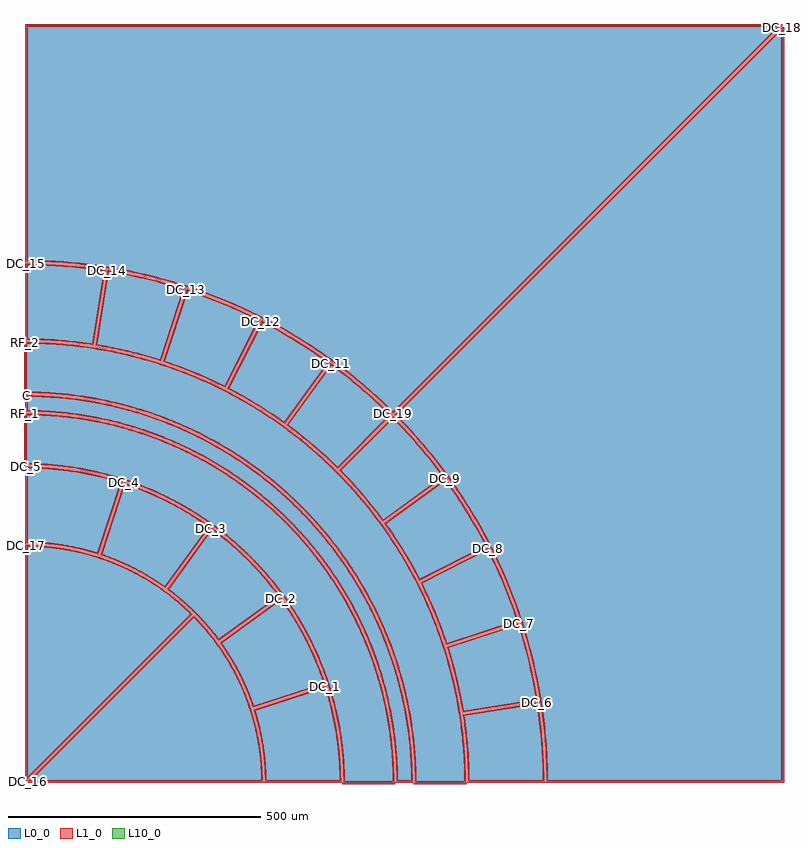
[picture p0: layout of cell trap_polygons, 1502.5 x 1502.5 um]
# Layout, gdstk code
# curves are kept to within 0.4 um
import gdstk
lib = gdstk.Library(unit=1e-6, precision=1e-09)
def P(c, l, *ps):  # polygons
    for p in ps: c.add(gdstk.Polygon(p, *l))
L0_0 = (0, 0)
L1_0 = (1, 0)
L10_0 = (10, 0)

trap_polygons = lib.new_cell('trap_polygons')
P(trap_polygons, L0_0, [(727.08,730.616),(691.717,764.181),(654.807,796.036),(609.899,830.945),(569.922,858.856),(528.671,884.846),(486.237,908.856),(442.715,930.833),(390.694,953.836),(345.151,971.245),(298.837,986.48),(251.854,999.508),(204.307,1010.299),(156.303,1018.83),(107.95,1025.082),(51.239,1029.476),(2.5,1030.747),(2.5,1497.5),(1493.964,1497.5)],
  [(1497.5,1493.964),(1497.5,2.5),(1030.747,2.5),(1029.476,51.239),(1025.082,107.95),(1018.83,156.303),(1010.299,204.307),(999.508,251.854),(986.48,298.837),(971.245,345.151),(953.836,390.694),(930.833,442.715),(908.856,486.237),(884.846,528.671),(858.856,569.922),(830.945,609.899),(796.036,654.807),(764.181,691.717),(730.616,727.08)],
  [(2.5,469.243),(28.188,468.403),(50.143,466.563),(71.986,463.695),(93.672,459.806),(115.15,454.902),(136.375,448.996),(160.754,440.856),(181.269,432.825),(201.385,423.839),(221.057,413.92),(240.241,403.088),(261.951,389.329),(279.936,376.605),(297.304,363.051),(314.017,348.696),(330.037,333.573),(2.5,6.036)],
  [(6.036,2.5),(333.573,330.037),(348.696,314.017),(363.051,297.304),(376.605,279.936),(389.329,261.951),(403.088,240.241),(413.92,221.057),(423.839,201.385),(432.825,181.269),(440.856,160.754),(448.996,136.375),(454.902,115.15),(459.806,93.672),(463.695,71.986),(466.563,50.143),(468.403,28.188),(469.243,2.5)],
  [(2.5,1025.747),(43.572,1024.824),(76.383,1022.902),(117.282,1019.023),(157.993,1013.509),(134.528,865.356),(99.959,870.027),(72.188,872.77),(37.374,874.952),(2.5,875.746)],
  [(162.931,1012.727),(203.354,1005.391),(235.46,998.36),(275.248,988.13),(314.596,976.316),(268.243,833.657),(234.831,843.678),(201.046,852.361),(173.786,858.334),(139.466,864.573)],
  [(319.351,974.771),(358.128,961.201),(396.33,946.09),(433.897,929.46),(463.452,915.082),(395.353,781.431),(370.254,793.631),(338.355,807.746),(305.919,820.58),(272.998,832.112)],
  [(467.907,912.812),(504.084,893.344),(539.452,872.442),(573.954,850.141),(600.896,831.316),(512.728,709.963),(484.048,729.819),(460.549,744.871),(430.52,762.621),(399.808,779.161)],
  [(604.941,828.377),(637.627,803.489),(669.29,777.312),(693.85,755.47),(723.545,727.08),(617.478,621.014),(592.258,645.112),(566.097,668.186),(544.52,685.884),(516.773,707.024)],
  [(727.08,723.545),(755.47,693.85),(777.312,669.29),(803.489,637.627),(828.377,604.941),(707.024,516.773),(685.884,544.52),(668.186,566.097),(645.112,592.258),(621.014,617.478)],
  [(831.316,600.896),(850.141,573.954),(872.442,539.452),(893.344,504.084),(912.812,467.907),(779.161,399.808),(762.621,430.52),(744.871,460.549),(729.819,484.048),(709.963,512.728)],
  [(915.082,463.452),(929.46,433.897),(946.09,396.33),(961.201,358.128),(974.771,319.351),(832.112,272.998),(820.58,305.919),(807.746,338.355),(793.631,370.254),(781.431,395.353)],
  [(976.316,314.596),(988.13,275.248),(998.36,235.46),(1005.391,203.354),(1012.727,162.931),(864.573,139.466),(858.334,173.786),(852.361,201.046),(843.678,234.831),(833.657,268.243)],
  [(1013.509,157.993),(1019.023,117.282),(1022.902,76.383),(1024.824,43.572),(1025.747,2.5),(875.746,2.5),(874.952,37.374),(872.77,72.188),(870.027,99.959),(865.356,134.528)],
  [(2.5,624.245),(26.993,623.666),(51.445,622.127),(95.233,616.943),(119.369,612.731),(143.32,607.575),(167.051,601.483),(190.525,594.465),(144.172,451.805),(108.597,461.649),(76.012,468.119),(39.375,472.613),(2.5,474.243)],
  [(195.28,592.92),(218.396,584.8),(241.175,575.78),(263.583,565.873),(285.585,555.094),(324.057,533.55),(344.744,520.423),(364.899,506.494),(276.731,385.14),(245.94,405.496),(213.659,423.395),(183.493,437.314),(148.927,450.26)],
  [(368.945,503.555),(403.571,476.255),(421.948,460.052),(439.675,443.141),(456.726,425.546),(473.072,407.297),(488.69,388.42),(503.555,368.945),(382.202,280.776),(361.607,306.844),(336.648,334.038),(309.65,359.207),(280.776,382.202)],
  [(506.494,364.899),(520.423,344.744),(533.55,324.057),(555.094,285.585),(565.873,263.583),(575.78,241.175),(584.8,218.396),(592.92,195.28),(450.26,148.927),(437.314,183.493),(423.395,213.659),(405.496,245.94),(385.14,276.731)],
  [(594.465,190.525),(601.483,167.051),(607.575,143.32),(612.731,119.369),(616.943,95.233),(622.127,51.445),(623.666,26.993),(624.245,2.5),(474.243,2.5),(472.613,39.375),(468.119,76.012),(461.649,108.597),(451.805,144.172)],
  [(2.5,765.746),(38.419,764.786),(80.212,761.537),(115.848,756.936),(151.229,750.668),(186.277,742.748),(226.642,731.441),(260.705,720.004),(294.194,706.981),(332.441,689.823),(364.435,673.469),(395.627,655.631),(425.947,636.35),(460.132,612.088),(488.339,589.829),(515.47,566.272),(541.467,541.467),(566.272,515.47),(589.829,488.339),(612.088,460.132),(636.35,425.947),(655.631,395.627),(673.469,364.435),(689.823,332.441),(706.981,294.194),(720.004,260.705),(731.441,226.642),(742.748,186.277),(750.668,151.229),(756.936,115.848),(761.537,80.212),(764.786,38.419),(765.746,2.5),(734.246,2.5),(733.009,42.668),(729.577,82.709),(723.959,122.502),(716.172,161.928),(706.24,200.869),(694.192,239.208),(680.065,276.83),(663.9,313.623),(648.46,344.417),(634.501,369.502),(616.472,398.855),(600.41,422.647),(579.926,450.343),(561.879,472.668),(542.973,494.27),(519.193,519.193),(494.27,542.973),(472.668,561.879),(450.343,579.926),(422.647,600.41),(398.855,616.472),(369.502,634.501),(344.417,648.46),(313.623,663.9),(276.83,680.065),(239.208,694.192),(200.869,706.24),(161.928,716.172),(122.502,723.959),(82.709,729.577),(42.668,733.009),(2.5,734.246)],
  [(0,870.75),(41.018,869.783),(81.945,866.886),(129.457,861.073),(169.875,854.019),(209.916,845.069),(256.036,832.257),(294.956,819.272),(333.222,804.468),(370.747,787.878),(407.45,769.539),(449.121,745.987),(483.763,724.002),(517.331,700.41),(549.75,675.263),(586.026,644.034),(615.713,615.713),(644.034,586.026),(675.263,549.75),(700.41,517.331),(724.002,483.763),(745.987,449.121),(769.539,407.45),(787.878,370.747),(804.468,333.222),(819.272,294.956),(832.257,256.036),(845.069,209.916),(854.019,169.875),(861.073,129.457),(866.886,81.945),(869.783,41.018),(870.75,0),(770.75,0),(769.894,36.307),(766.736,78.558),(762.184,114.589),(755.94,150.366),(748.018,185.809),(738.435,220.839),(727.212,255.379),(712.08,294.953),(694.797,333.637),(678.309,365.996),(660.315,397.542),(640.855,428.206),(619.973,457.919),(593.873,491.295),(570.071,518.724),(545.003,545.003),(518.724,570.071),(491.295,593.873),(457.919,619.973),(428.206,640.855),(397.542,660.315),(365.996,678.309),(333.637,694.797),(294.953,712.08),(255.379,727.212),(220.839,738.435),(185.809,748.018),(150.366,755.94),(114.589,762.184),(78.558,766.736),(36.307,769.894),(0,770.75)],
  [(0,729.25),(34.352,728.44),(68.628,726.014),(102.752,721.975),(142.27,715.238),(175.804,707.742),(208.948,698.675),(247.025,686.137),(279.072,673.739),(310.5,659.845),(341.238,644.486),(376.137,624.761),(405.15,606.349),(433.263,586.591),(464.841,561.897),(490.794,539.376),(515.658,515.658),(539.376,490.794),(561.897,464.841),(586.591,433.263),(606.349,405.15),(624.761,376.137),(644.486,341.238),(659.845,310.5),(673.739,279.072),(686.137,247.025),(698.675,208.948),(707.742,175.804),(715.238,142.27),(721.975,102.752),(726.014,68.628),(728.44,34.352),(729.25,0),(629.25,0),(628.299,34.577),(625.973,64.136),(622.257,93.552),(617.159,122.761),(609.481,156.488),(601.433,185.025),(592.049,213.151),(581.351,240.804),(569.362,267.922),(556.11,294.445),(541.622,320.314),(523.202,349.593),(506.153,373.851),(487.981,397.279),(468.725,419.825),(444.947,444.947),(419.825,468.725),(397.279,487.981),(373.851,506.153),(349.593,523.202),(320.314,541.622),(294.445,556.11),(267.922,569.362),(240.804,581.351),(213.151,592.049),(185.025,601.433),(156.488,609.481),(122.761,617.159),(93.552,622.257),(64.136,625.973),(34.577,628.299),(0,629.25)])
P(trap_polygons, L1_0, [(404.701,950.689),(353.654,970.842),(307.349,986.48),(260.356,999.91),(212.781,1011.103),(164.73,1020.034),(108.211,1027.568),(59.498,1031.536),(5,1033.231),(5,1495),(404.701,1495),(404.701,1500),(0,1500),(0,1028.263),(51.115,1026.979),(99.622,1023.413),(147.906,1017.557),(195.859,1009.424),(251.243,997.083),(305.862,981.706),(351.943,966.144),(404.701,945.259)],
  [(727.081,730.616),(728.848,728.848),(1497.5,1497.5),(1496.464,1500),(404.701,1500),(404.701,1495),(1487.929,1495),(727.069,734.14),(693.395,766.034),(656.395,797.967),(617.926,828.114),(578.075,856.408),(536.93,882.786),(494.584,907.189),(451.131,929.562),(404.701,950.689),(404.701,945.259),(456.228,921.496),(499.293,898.891),(541.242,874.274),(581.979,847.702),(614.936,824.107),(646.937,799.231),(684.008,767.744),(725.324,728.837)],
  [(1500,399.168),(1495,399.168),(1495,5),(1033.231,5),(1031.536,59.498),(1026.683,116.31),(1018.704,172.767),(1009.394,220.746),(995.681,276.09),(986.48,307.349),(976.298,338.302),(965.145,368.918),(953.032,399.168),(947.603,399.168),(966.144,351.943),(981.706,305.862),(997.083,251.243),(1007.849,203.811),(1017.557,147.906),(1023.413,99.622),(1026.979,51.115),(1028.263,0),(1500,0)],
  [(1500,1493.964),(1497.501,1493.964),(1495.732,1495.732),(727.092,727.092),(762.327,690.04),(794.105,653.219),(824.107,614.936),(852.264,575.278),(878.514,534.332),(902.799,492.191),(925.064,448.948),(947.603,399.168),(953.032,399.168),(939.972,429.02),(925.977,458.446),(899.278,508.827),(882.786,536.93),(865.417,564.499),(832.96,611.378),(803.117,650.083),(771.478,687.334),(734.14,727.069),(1495,1487.929),(1495,399.168),(1500,399.168)],
  [(333.573,333.573),(312.937,353.014),(293.139,369.618),(272.462,385.114),(250.967,399.454),(222.234,416.125),(189.023,432.225),(186.566,433.288),(173.543,433.288),(197.007,423.136),(216.65,413.423),(235.816,402.798),(254.462,391.286),(272.548,378.911),(292.885,363.42),(309.62,349.272),(326.485,333.556),(5,12.071),(5,433.288),(0,433.288),(0,3.536),(2.5,2.5)],
  [(185.634,433.691),(161.61,443.204),(137.101,451.388),(112.181,458.218),(86.924,463.673),(57.745,468.203),(32.023,470.662),(2.523,471.743),(2.5,469.243),(0,469.243),(0,433.288),(5,433.288),(5,466.72),(42.606,464.801),(60.756,462.779),(82.41,459.417),(103.883,455.043),(128.642,448.672),(149.56,442.14),(173.543,433.288),(186.566,433.288)],
  [(334.355,325.672),(349.272,309.62),(365.701,290.032),(378.911,272.548),(391.286,254.462),(402.798,235.816),(413.423,216.65),(423.136,197.007),(432.225,176.166),(432.225,189.023),(416.125,222.234),(399.454,250.967),(385.114,272.462),(369.618,293.139),(353.014,312.937),(333.573,333.573),(4.268,4.268),(6.036,2.499),(6.036,0),(432.225,0),(432.225,5),(12.071,5),(333.556,326.485)],
  [(471.766,0.023),(471.105,24.653),(469.049,50.41),(466.166,72.37),(461.504,97.785),(456.406,119.339),(449.187,144.149),(440.621,168.527),(432.225,189.023),(432.225,176.166),(440.956,153.015),(447.652,132.149),(454.216,107.441),(458.758,86.003),(462.289,64.376),(464.454,46.242),(466.112,24.391),(466.72,5),(432.225,5),(432.225,0)],
  [(2.516,1028.247),(2.484,1023.247),(35.275,1022.642),(76.197,1020.409),(116.996,1016.539),(155.13,1011.415),(132.447,868.199),(100.245,872.51),(65.419,875.81),(37.48,877.45),(5,878.229),(5,1025.747),(0,1025.747),(0,873.263),(30.315,872.724),(65.046,870.824),(99.674,867.543),(136.609,862.512),(160.84,1015.606),(125.747,1020.532),(84.781,1024.749),(43.678,1027.322)],
  [(163.338,1015.194),(162.524,1010.261),(194.817,1004.533),(234.886,995.926),(274.578,985.722),(311.44,974.695),(266.633,836.791),(235.501,846.086),(201.62,854.794),(174.282,860.784),(142.324,866.635),(165.401,1012.336),(160.462,1013.118),(136.609,862.512),(173.29,855.883),(207.237,848.303),(240.855,839.377),(269.853,830.523),(317.735,977.941),(283.845,988.296),(244.043,998.87),(203.849,1007.841)],
  [(320.139,977.143),(318.563,972.398),(349.562,961.69),(387.791,946.921),(425.398,930.633),(460.082,913.975),(394.253,784.778),(364.959,798.829),(332.857,812.73),(306.793,822.922),(276.143,833.701),(321.729,973.998),(316.973,975.543),(269.853,830.523),(298.518,820.642),(330.962,808.103),(362.881,794.281),(396.453,778.083),(466.807,916.196),(434.954,931.726),(397.296,948.395),(359.001,963.544)],
  [(469.056,915.032),(466.758,910.592),(495.7,895.166),(531.148,874.598),(565.744,852.628),(597.395,830.75),(512.165,713.441),(485.43,731.902),(455.898,750.653),(431.749,764.798),(403.163,780.238),(470.134,911.677),(465.679,913.947),(396.453,778.083),(429.291,760.444),(459.234,742.745),(488.449,723.867),(513.291,706.485),(604.385,831.892),(575.353,852.213),(540.766,874.568),(505.312,895.521)],
  [(606.424,830.39),(603.459,826.364),(636.073,801.531),(661.426,780.741),(692.159,753.629),(719.998,727.069),(617.466,624.537),(593.948,646.953),(567.713,670.093),(546.074,687.842),(520.255,707.564),(606.964,826.908),(602.919,829.847),(513.291,706.485),(542.965,683.926),(569.771,661.76),(595.673,638.545),(617.491,617.491),(727.08,727.103),(701.585,751.716),(670.921,779.206),(639.181,805.447)],
  [(728.86,725.301),(725.301,721.789),(753.629,692.159),(775.417,667.659),(801.531,636.073),(824.872,605.485),(707.564,520.255),(687.842,546.074),(670.093,567.713),(646.953,593.948),(624.537,617.466),(728.848,721.777),(725.313,725.313),(617.491,617.491),(638.545,595.673),(661.76,569.771),(683.926,542.965),(706.485,513.291),(831.873,604.411),(810.542,632.709),(784.556,664.658),(757.312,695.541)],
  [(833.348,602.353),(829.284,599.44),(848.069,572.556),(870.316,538.137),(891.166,502.855),(909.435,468.992),(780.238,403.163),(764.798,431.749),(750.653,455.898),(731.902,485.43),(713.441,512.165),(832.786,598.874),(829.847,602.919),(706.485,513.291),(723.867,488.449),(742.745,459.234),(760.444,429.291),(778.083,396.453),(916.182,466.836),(899.54,498.122),(878.872,533.743),(856.794,568.508)],
  [(917.317,464.572),(912.847,462.331),(930.633,425.398),(943.784,395.364),(958.858,357.255),(971.605,320.951),(833.701,276.143),(822.922,306.793),(812.73,332.857),(798.829,364.959),(784.778,394.253),(916.217,461.224),(913.947,465.679),(778.083,396.453),(794.281,362.881),(808.103,330.962),(820.642,298.518),(830.523,269.853),(977.931,317.766),(966.389,351.27),(951.548,389.686),(935.18,427.477)],
  [(978.698,315.353),(973.933,313.838),(983.491,282.465),(994.013,242.856),(1002.94,202.858),(1009.851,165.007),(866.635,142.324),(860.784,174.282),(854.794,201.62),(846.086,235.501),(836.791,266.633),(977.088,312.218),(975.543,316.973),(830.523,269.853),(839.377,240.855),(848.303,207.237),(855.883,173.29),(862.512,136.609),(1015.601,160.872),(1009.442,195.769),(1000.793,236.034),(990.539,275.919)],
  [(1015.981,158.368),(1011.038,157.618),(1015.57,125.136),(1019.766,84.369),(1022.326,43.466),(1023.231,5),(878.229,5),(877.45,37.48),(875.81,65.419),(872.51,100.245),(868.199,132.447),(1013.9,155.524),(1013.118,160.462),(862.512,136.609),(867.543,99.674),(870.824,65.046),(872.724,30.315),(873.263,0),(1028.263,0.016),(1027.639,35.447),(1025.395,76.569),(1021.507,117.568)],
  [(2.52,626.745),(2.48,621.745),(26.885,621.168),(51.239,619.635),(94.852,614.472),(118.891,610.277),(142.746,605.142),(166.382,599.074),(187.368,592.841),(142.559,454.933),(109.17,464.082),(76.412,470.587),(39.583,475.104),(5,476.721),(5,624.245),(0,624.245),(0,471.766),(35.507,470.412),(71.984,466.226),(108.025,459.215),(145.784,448.676),(193.662,596.095),(172.456,602.557),(148.678,608.86),(124.672,614.225),(100.474,618.644),(76.121,622.11),(51.651,624.618),(27.101,626.164)],
  [(196.071,595.291),(194.489,590.548),(235.7,575.342),(258.095,565.65),(280.092,555.087),(301.658,543.669),(322.759,531.413),(343.363,518.339),(361.396,505.925),(276.164,388.614),(247.236,407.633),(214.785,425.627),(184.461,439.619),(152.07,451.843),(197.658,592.147),(192.902,593.692),(145.784,448.676),(179.134,436.416),(212.532,421.163),(244.643,403.358),(277.297,381.667),(368.387,507.075),(350.215,519.774),(329.55,533.116),(308.376,545.637),(286.728,557.317),(264.638,568.139),(242.141,578.086),(219.27,587.142)],
  [(370.43,505.566),(367.459,501.545),(386.864,486.733),(405.666,471.178),(437.915,441.366),(454.897,423.842),(471.178,405.666),(486.733,386.864),(500.047,369.486),(382.736,284.254),(361.101,311.282),(338.423,335.798),(311.282,361.101),(284.254,382.736),(370.967,502.086),(366.922,505.025),(277.297,381.667),(305.227,359.701),(332.277,334.874),(357.314,308.018),(381.667,277.297),(507.052,368.419),(493.693,386.112),(478.162,405.187),(461.894,423.638),(444.915,441.436),(427.251,458.555),(408.928,474.967),(389.975,490.647)],
  [(508.528,366.353),(504.46,363.446),(528.863,326.921),(541.284,305.916),(552.871,284.441),(563.607,262.527),(573.474,240.209),(582.458,217.521),(589.751,196.879),(451.843,152.07),(439.619,184.461),(425.627,214.785),(407.633,247.236),(388.614,276.164),(507.964,362.877),(505.025,366.922),(381.667,277.297),(403.358,244.643),(421.163,212.532),(436.416,179.134),(448.676,145.784),(596.083,193.7),(588.846,214.655),(579.969,237.595),(570.199,260.17),(559.551,282.345),(548.041,304.084),(535.686,325.355),(522.507,346.124)],
  [(596.849,191.278),(592.081,189.771),(604.003,147.492),(609.325,123.678),(613.709,99.673),(617.147,75.514),(619.635,51.239),(621.168,26.885),(621.725,5),(476.721,5),(475.104,39.583),(470.587,76.412),(464.082,109.17),(454.933,142.559),(595.237,188.147),(593.692,192.902),(448.676,145.784),(459.215,108.025),(466.226,71.984),(470.412,35.507),(471.766,0),(626.765,0.02),(626.357,22.185),(625.004,46.746),(622.689,71.235),(619.414,95.615),(615.185,119.847),(610.008,143.894),(603.892,167.72)],
  [(229.099,700.224),(201.553,708.645),(173.698,715.982),(145.578,722.224),(117.235,727.363),(88.713,731.39),(60.055,734.298),(31.306,736.085),(5,736.728),(5,763.228),(32.33,762.565),(62.119,760.718),(85.884,758.403),(115.47,754.465),(144.879,749.374),(174.066,743.136),(202.987,735.763),(229.099,728.049),(229.099,733.29),(210.103,738.962),(181.051,746.611),(151.723,753.119),(122.162,758.475),(98.377,761.925),(68.513,765.189),(32.542,767.56),(2.518,768.246),(2.5,765.746),(0,765.746),(0,731.764),(48.234,730.159),(71.046,728.293),(99.461,724.959),(133.354,719.496),(166.953,712.45),(200.185,703.835),(229.099,694.957)],
  [(439.716,629.959),(417.299,645.034),(391.762,660.856),(365.625,675.667),(338.929,689.446),(311.715,702.169),(284.024,713.82),(255.899,724.378),(229.099,733.29),(229.099,728.049),(259.854,717.653),(293.234,704.673),(325.968,690.142),(352.701,676.87),(378.895,662.563),(399.434,650.387),(439.716,623.857)],
  [(439.716,591.137),(414.613,609.013),(390.49,624.755),(365.77,639.541),(340.491,653.35),(314.691,666.161),(288.411,677.953),(256.296,690.734),(229.099,700.224),(229.099,694.957),(259.913,684.034),(291.71,671.091),(322.865,656.671),(353.309,640.805),(373.177,629.442),(397.497,614.373),(421.208,598.366),(439.716,584.9)],
  [(606.484,471.575),(587.905,494.546),(568.12,517.153),(551.666,534.671),(530.34,555.831),(508.203,576.14),(485.29,595.569),(461.634,614.087),(439.716,629.959),(439.716,623.857),(468.116,602.841),(491.327,584.079),(513.787,564.423),(539.699,539.699),(556.317,522.553),(576.322,500.404),(606.484,463.387)],
  [(606.484,418.296),(588.896,442.721),(571.141,465.402),(548.684,491.678),(529.045,512.75),(508.597,533.038),(487.372,552.512),(465.402,571.141),(439.716,591.137),(439.716,584.9),(462.244,567.264),(488.341,544.96),(513.363,521.456),(537.256,496.804),(556.265,475.423),(574.424,453.315),(591.705,430.515),(606.484,409.423)],
  [(711.71,289.265),(702.169,311.715),(689.446,338.929),(675.667,365.625),(663.9,386.581),(651.483,407.159),(635.066,432.318),(606.484,471.575),(606.484,463.387),(624.137,439.321),(640.836,414.584),(656.555,389.212),(671.27,363.245),(692.67,320.56),(711.71,275.707)],
  [(711.71,190.445),(703.722,218.12),(692.717,250.886),(682.38,277.773),(668.601,309.472),(655.993,335.371),(639.541,365.77),(624.755,390.49),(606.484,418.296),(606.484,409.423),(626.504,378.088),(643.548,348.287),(659.175,317.72),(673.352,286.453),(686.046,254.556),(695.472,227.544),(703.835,200.185),(711.71,170.057)],
  [(768.264,0.018),(767.282,38.544),(764.63,74.496),(760.293,110.283),(754.283,145.828),(746.611,181.051),(737.296,215.876),(726.358,250.225),(711.71,289.265),(711.71,275.707),(723.552,242.945),(732.498,214.471),(740.323,185.669),(747.016,156.583),(751.548,133.139),(756.179,103.654),(759.051,79.95),(761.596,50.213),(763.228,5),(736.728,5),(736.085,31.306),(734.745,54.311),(729.913,100.14),(722.224,145.578),(711.71,190.445),(711.71,170.057),(717.323,144.59),(721.494,122.085),(727.715,76.739),(730.824,36.809),(731.764,0)],
  [(248.85,732.108),(215.73,742.547),(186.411,750.444),(156.805,757.184),(126.957,762.756),(96.914,767.153),(66.721,770.366),(36.425,772.392),(2.5,773.24),(2.5,868.24),(54.518,866.537),(81.71,864.397),(108.821,861.404),(149.277,855.321),(182.742,848.801),(215.925,840.972),(248.85,831.824),(248.85,837.037),(217.168,845.815),(183.794,853.689),(150.137,860.247),(116.248,865.478),(82.18,869.375),(41.136,872.281),(0.01,873.25),(0,870.75),(-2.5,870.75),(-2.5,768.26),(24.131,767.871),(54.259,766.332),(78.303,764.249),(108.247,760.586),(143.956,754.642),(179.344,747.023),(214.335,737.746),(248.85,726.83)],
  [(479.434,729.869),(450.41,748.129),(426.689,761.907),(396.447,778.071),(365.595,793.036),(334.178,806.778),(308.672,816.877),(276.364,828.365),(248.85,837.037),(248.85,831.824),(281.241,821.439),(313.274,809.764),(351.071,794.108),(381.977,779.712),(406.28,767.329),(430.182,754.189),(453.659,740.305),(479.434,723.871)],
  [(479.434,606.674),(454.505,625.572),(424.532,646.288),(393.616,665.569),(367.183,680.509),(340.183,694.4),(307.095,709.654),(278.997,721.163),(248.85,732.108),(248.85,726.83),(277.193,716.5),(305.109,705.065),(337.983,689.91),(364.808,676.109),(396.253,658.173),(421.787,642.109),(451.566,621.527),(479.434,600.288)],
  [(659.55,572.328),(641.247,592.763),(622.312,612.612),(597.781,636.572),(577.491,655.035),(556.631,672.851),(529.785,694.185),(507.719,710.484),(479.434,729.869),(479.434,723.871),(510.345,702.429),(537.528,681.851),(563.883,660.222),(589.369,637.576),(623.513,604.226),(642.185,584.343),(659.55,564.664)],
  [(659.55,403.617),(642.934,429.595),(621.983,459.404),(599.652,488.194),(580.023,511.359),(555.291,538.115),(533.737,559.5),(506.788,584.022),(479.434,606.674),(479.434,600.288),(503.511,580.245),(530.286,555.882),(551.701,534.635),(576.273,508.053),(599.566,480.343),(621.527,451.566),(642.109,421.787),(659.55,393.945)],
  [(764.84,421.403),(740.962,462.106),(714.449,502.123),(685.778,540.624),(659.55,572.328),(659.55,564.664),(690.21,526.752),(718.113,488.029),(743.845,447.831),(764.84,410.937)],
  [(764.84,113.71),(758.392,150.854),(750.444,186.411),(739.067,227.367),(727.536,261.929),(712.044,301.512),(697.05,334.719),(680.509,367.183),(659.55,403.617),(659.55,393.945),(681.755,354.144),(700.186,316.146),(718.655,271.557),(732.491,231.657),(742.591,196.894),(752.288,155.791),(759.712,114.218),(764.84,72.299)],
  [(873.26,-2.49),(872.819,27.429),(871.527,54.832),(869.375,82.18),(866.364,109.447),(862.499,136.606),(857.782,163.631),(852.219,190.494),(845.815,217.168),(838.576,243.629),(830.51,269.849),(821.624,295.803),(811.927,321.465),(801.429,346.809),(790.14,371.812),(778.071,396.447),(764.84,421.403),(764.84,410.937),(779.712,381.977),(791.326,357.297),(804.743,325.955),(814.585,300.516),(829.867,255.301),(842.642,209.313),(852.871,162.694),(857.56,135.824),(861.404,108.821),(864.397,81.71),(866.537,54.518),(868.223,6.819),(868.24,2.5),(773.24,2.5),(772.654,30.358),(770.866,60.668),(768.58,84.852),(764.84,113.71),(764.84,72.299),(767.397,36.19),(768.26,-2.5)],
  [(204.635,597.689),(181.012,605.263),(157.11,611.902),(132.966,617.599),(103.725,623.177),(79.179,626.768),(54.511,629.394),(29.76,631.049),(2.5,631.74),(2.5,726.74),(28.532,726.19),(51.328,724.935),(74.074,722.965),(102.4,719.5),(130.568,714.925),(152.96,710.471),(180.735,703.918),(204.635,697.339),(204.635,702.553),(176.407,710.168),(148.39,716.546),(120.144,721.82),(91.713,725.98),(57.412,729.494),(22.985,731.389),(0.01,731.75),(0,729.25),(-2.5,729.25),(-2.5,626.76),(19.687,626.441),(44.265,625.185),(88.31,620.497),(117.441,615.649),(146.312,609.433),(174.858,601.864),(204.635,592.397)],
  [(395.7,615.527),(372.491,629.848),(347.476,643.986),(327.077,654.583),(301.126,666.919),(280.029,676.049),(253.271,686.522),(231.582,694.138),(204.635,702.553),(204.635,697.339),(235.407,687.568),(262.219,677.795),(293.857,664.691),(319.726,652.642),(360.075,631.278),(395.7,609.573)],
  [(395.7,492.469),(375.336,508.164),(350.982,525.281),(325.848,541.231),(304.348,553.607),(282.379,565.129),(255.444,577.803),(227.942,589.195),(204.635,597.689),(204.635,592.397),(235.292,580.907),(262.395,569.179),(288.916,556.186),(314.795,541.959),(335.829,529.183),(356.346,515.59),(376.313,501.202),(395.7,486.042)],
  [(544.415,488.943),(525.489,509.234),(509.234,525.489),(475.234,556.427),(453.022,574.656),(434.748,588.602),(395.7,615.527),(395.7,609.573),(417.885,594.59),(440.906,577.726),(463.248,559.97),(484.875,541.352),(513.89,513.89),(544.415,481.427)],
  [(544.415,320.493),(530.729,342.687),(513.997,367.308),(496.124,391.113),(477.149,414.049),(460.526,432.463),(439.643,453.676),(417.784,473.883),(395.7,492.469),(395.7,486.042),(421.811,463.564),(443.179,443.179),(463.564,421.811),(486.042,395.7),(501.202,376.313),(518.373,352.286),(531.804,331.663),(544.415,310.529)],
  [(626.441,378.187),(608.428,406.539),(588.602,434.748),(567.469,461.992),(544.415,488.943),(544.415,481.427),(567.178,454.395),(587.953,427.173),(607.423,399.002),(626.441,368.415)],
  [(626.441,81.689),(621.471,113.501),(615.434,142.65),(606.666,176.253),(597.689,204.635),(585.542,237.169),(573.719,264.488),(560.623,291.221),(544.415,320.493),(544.415,310.529),(562.839,275.732),(579.041,239.847),(592.959,203.015),(604.536,165.382),(612.711,131.913),(619.785,93.18),(624.412,54.08),(626.441,19.687)],
  [(731.76,-2.49),(730.306,45.947),(727.939,74.583),(725.237,97.412),(717.69,142.757),(711.532,170.824),(705.815,193.089),(699.402,215.164),(690.415,242.457),(682.459,264.023),(671.567,290.613),(659.64,316.755),(649.365,337.318),(626.441,378.187),(626.441,368.415),(639.586,345.102),(652.642,319.726),(664.691,293.857),(675.715,267.535),(689.395,230),(702.477,186.258),(712.786,141.782),(720.282,96.746),(724.935,51.328),(726.19,28.532),(726.74,2.5),(631.74,2.5),(630.172,44.619),(626.441,81.689),(626.76,-2.5)])
P(trap_polygons, L10_0, [(0,0),(0,0),(0,0),(0,0)])
trap_polygons.add(gdstk.Label('DC_19', (727.08,730.616), layer=2, texttype=0))
trap_polygons.add(gdstk.Label('DC_18', (1497.5,1493.964), layer=2, texttype=0))
trap_polygons.add(gdstk.Label('DC_17', (2.5,469.243), layer=2, texttype=0))
trap_polygons.add(gdstk.Label('DC_16', (6.036,2.5), layer=2, texttype=0))
trap_polygons.add(gdstk.Label('DC_15', (2.5,1025.747), layer=2, texttype=0))
trap_polygons.add(gdstk.Label('DC_14', (162.931,1012.727), layer=2, texttype=0))
trap_polygons.add(gdstk.Label('DC_13', (319.351,974.771), layer=2, texttype=0))
trap_polygons.add(gdstk.Label('DC_12', (467.907,912.812), layer=2, texttype=0))
trap_polygons.add(gdstk.Label('DC_11', (604.941,828.377), layer=2, texttype=0))
trap_polygons.add(gdstk.Label('DC_10', (727.08,723.545), layer=2, texttype=0))
trap_polygons.add(gdstk.Label('DC_9', (831.316,600.896), layer=2, texttype=0))
trap_polygons.add(gdstk.Label('DC_8', (915.082,463.452), layer=2, texttype=0))
trap_polygons.add(gdstk.Label('DC_7', (976.316,314.596), layer=2, texttype=0))
trap_polygons.add(gdstk.Label('DC_6', (1013.509,157.993), layer=2, texttype=0))
trap_polygons.add(gdstk.Label('DC_5', (2.5,624.245), layer=2, texttype=0))
trap_polygons.add(gdstk.Label('DC_4', (195.28,592.92), layer=2, texttype=0))
trap_polygons.add(gdstk.Label('DC_3', (368.945,503.555), layer=2, texttype=0))
trap_polygons.add(gdstk.Label('DC_2', (506.494,364.899), layer=2, texttype=0))
trap_polygons.add(gdstk.Label('DC_1', (594.465,190.525), layer=2, texttype=0))
trap_polygons.add(gdstk.Label('C', (2.5,765.746), layer=2, texttype=0))
trap_polygons.add(gdstk.Label('RF_2', (0,870.75), layer=2, texttype=0))
trap_polygons.add(gdstk.Label('RF_1', (0,729.25), layer=2, texttype=0))

lib.write_gds('trap_polygons.gds')
